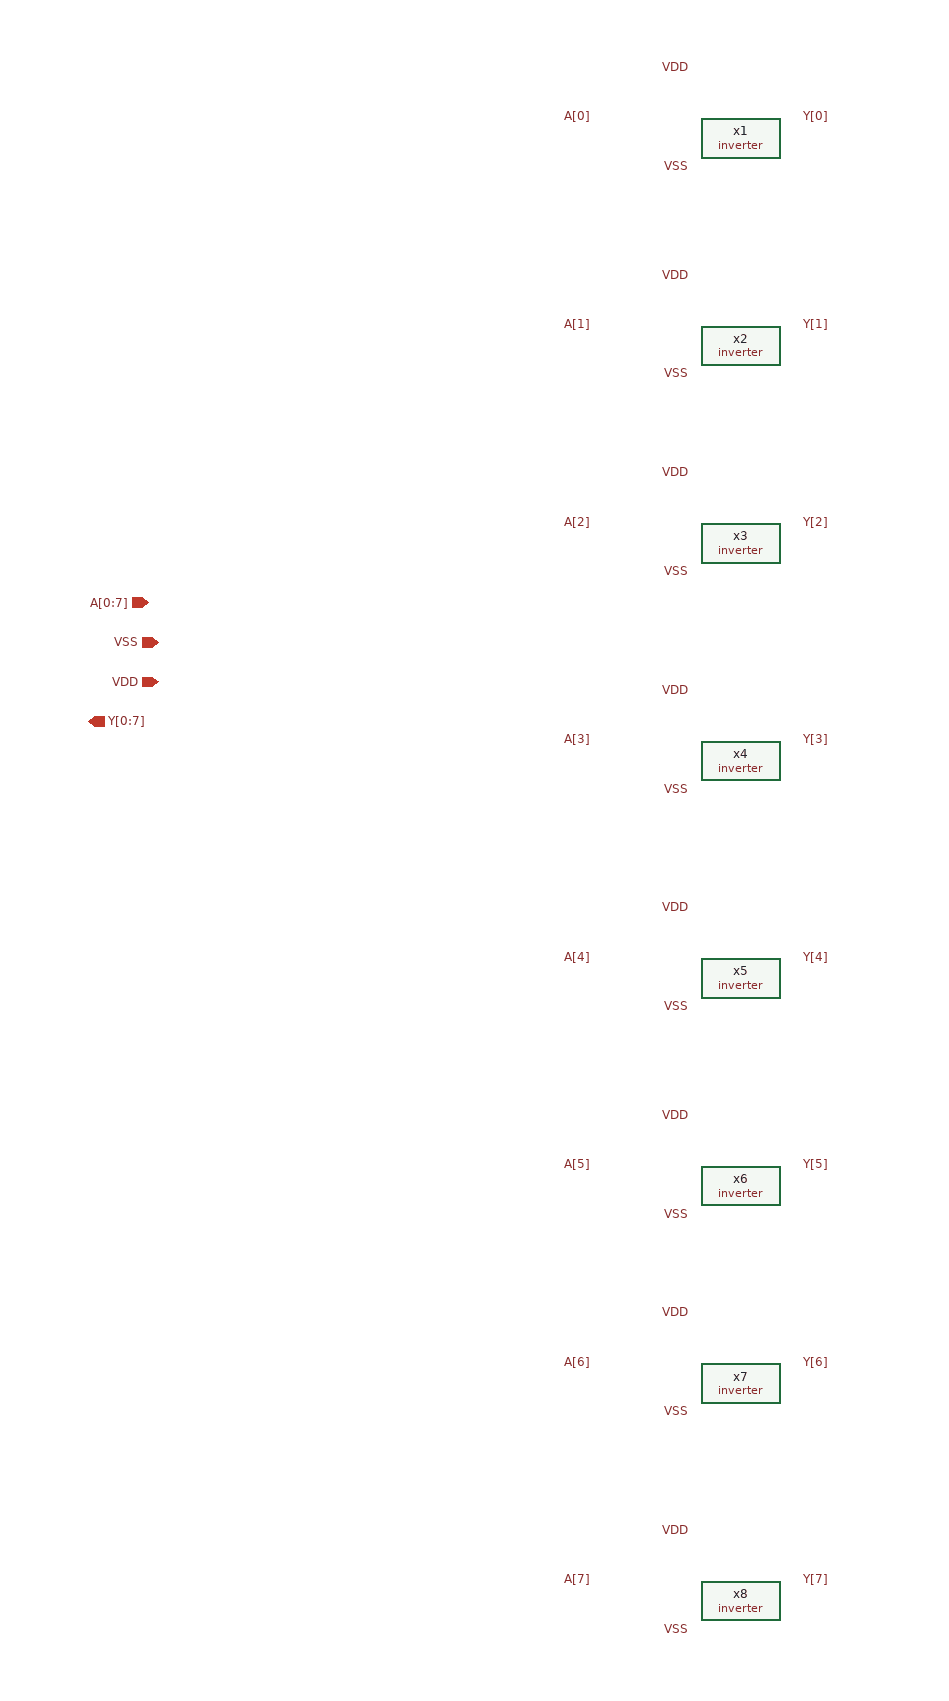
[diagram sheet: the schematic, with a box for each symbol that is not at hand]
v {xschem version=3.1.0 file_version=1.2 }
G {}
K {}
V {}
S {}
E {}
C {inverter.sym} 50 -40 0 0 {name=x1}
C {inverter.sym} 50 170 0 0 {name=x2}
C {inverter.sym} 50 370 0 0 {name=x3}
C {inverter.sym} 50 590 0 0 {name=x4}
C {devices/ipin.sym} -550 430 0 0 {name=p3 lab=A[0:7]}
C {devices/opin.sym} -610 550 0 0 {name=p9 lab=Y[0:7]}
C {devices/iopin.sym} -540 470 2 0 {name=p6 lab=VSS}
C {devices/iopin.sym} -540 510 2 0 {name=p7 lab=VDD}
C {devices/lab_pin.sym} 0 200 3 0 {name=l83 sig_type=std_logic lab=VSS}
C {devices/lab_pin.sym} 0 400 3 0 {name=l4 sig_type=std_logic lab=VSS}
C {devices/lab_pin.sym} 0 620 3 0 {name=l5 sig_type=std_logic lab=VSS}
C {devices/lab_pin.sym} 0 -10 3 0 {name=l6 sig_type=std_logic lab=VSS}
C {devices/lab_pin.sym} -100 -60 0 0 {name=l12 sig_type=std_logic lab=A[0]}
C {devices/lab_pin.sym} -100 150 0 0 {name=l7 sig_type=std_logic lab=A[1]}
C {devices/lab_pin.sym} -100 350 0 0 {name=l8 sig_type=std_logic lab=A[2]}
C {devices/lab_pin.sym} -100 570 0 0 {name=l9 sig_type=std_logic lab=A[3]}
C {devices/lab_pin.sym} 110 -60 2 0 {name=l27 sig_type=std_logic lab=Y[0]}
C {devices/lab_pin.sym} 110 150 2 0 {name=l10 sig_type=std_logic lab=Y[1]}
C {devices/lab_pin.sym} 110 350 2 0 {name=l11 sig_type=std_logic lab=Y[2]}
C {devices/lab_pin.sym} 110 570 2 0 {name=l13 sig_type=std_logic lab=Y[3]}
C {devices/lab_pin.sym} 0 520 1 0 {name=l15 sig_type=std_logic lab=VDD}
C {devices/lab_pin.sym} 0 300 1 0 {name=l1 sig_type=std_logic lab=VDD}
C {devices/lab_pin.sym} 0 100 1 0 {name=l2 sig_type=std_logic lab=VDD}
C {devices/lab_pin.sym} 0 -110 1 0 {name=l3 sig_type=std_logic lab=VDD}
C {inverter.sym} 50 810 0 0 {name=x5}
C {inverter.sym} 50 1020 0 0 {name=x6}
C {inverter.sym} 50 1220 0 0 {name=x7}
C {inverter.sym} 50 1440 0 0 {name=x8}
C {devices/lab_pin.sym} 0 1050 3 0 {name=l14 sig_type=std_logic lab=VSS}
C {devices/lab_pin.sym} 0 1250 3 0 {name=l16 sig_type=std_logic lab=VSS}
C {devices/lab_pin.sym} 0 1470 3 0 {name=l17 sig_type=std_logic lab=VSS}
C {devices/lab_pin.sym} 0 840 3 0 {name=l18 sig_type=std_logic lab=VSS}
C {devices/lab_pin.sym} -100 790 0 0 {name=l19 sig_type=std_logic lab=A[4]}
C {devices/lab_pin.sym} -100 1000 0 0 {name=l20 sig_type=std_logic lab=A[5]}
C {devices/lab_pin.sym} -100 1200 0 0 {name=l21 sig_type=std_logic lab=A[6]}
C {devices/lab_pin.sym} -100 1420 0 0 {name=l22 sig_type=std_logic lab=A[7]}
C {devices/lab_pin.sym} 110 790 2 0 {name=l23 sig_type=std_logic lab=Y[4]}
C {devices/lab_pin.sym} 110 1000 2 0 {name=l24 sig_type=std_logic lab=Y[5]}
C {devices/lab_pin.sym} 110 1200 2 0 {name=l25 sig_type=std_logic lab=Y[6]}
C {devices/lab_pin.sym} 110 1420 2 0 {name=l26 sig_type=std_logic lab=Y[7]}
C {devices/lab_pin.sym} 0 1370 1 0 {name=l28 sig_type=std_logic lab=VDD}
C {devices/lab_pin.sym} 0 1150 1 0 {name=l29 sig_type=std_logic lab=VDD}
C {devices/lab_pin.sym} 0 950 1 0 {name=l30 sig_type=std_logic lab=VDD}
C {devices/lab_pin.sym} 0 740 1 0 {name=l31 sig_type=std_logic lab=VDD}
